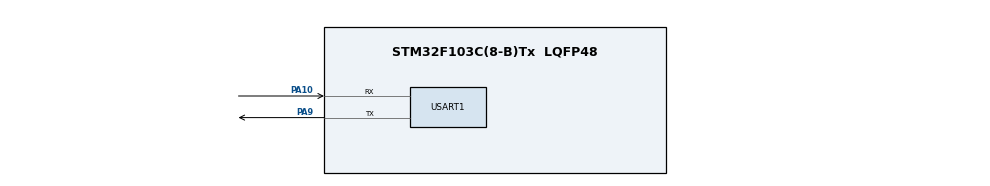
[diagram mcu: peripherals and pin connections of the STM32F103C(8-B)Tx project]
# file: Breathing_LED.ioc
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Mcu.Family=STM32F1
Mcu.Name=STM32F103C(8-B)Tx
Mcu.Package=LQFP48
NVIC.PriorityGroup=NVIC_PRIORITYGROUP_4
PA1.Signal=S_TIM2_CH2
PA10.Mode=Asynchronous
PA10.Signal=USART1_RX
PA13.Mode=Serial_Wire
PA13.Signal=SYS_JTMS-SWDIO
PA14.Mode=Serial_Wire
PA14.Signal=SYS_JTCK-SWCLK
PA9.Mode=Asynchronous
PA9.Signal=USART1_TX
PD0-OSC_IN.Mode=HSE-External-Oscillator
PD0-OSC_IN.Signal=RCC_OSC_IN
PD1-OSC_OUT.Mode=HSE-External-Oscillator
PD1-OSC_OUT.Signal=RCC_OSC_OUT
ProjectManager.HeapSize=0x200
Pr

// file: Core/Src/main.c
/* USER CODE BEGIN Header */
/**
  ******************************************************************************
  * @file           : main.c
  * @brief          : Main program body
  ******************************************************************************
  * @attention
  *
  * Copyright (c) 2026 STMicroelectronics.
  * All rights reserved.
  *
  * This software is licensed under terms that can be found in the LICENSE file
  * in the root directory of this software component.
  * If no LICENSE file comes with this software, it is provided AS-IS.
  *
  ******************************************************************************
  */
/* USER CODE END Header */
#include "main.h"
#include "tim.h"
#include "usart.h"
#include "gpio.h"

/* USER CODE BEGIN Includes */
#include <stdio.h>
/* USER CODE END Includes */

/* USER CODE BEGIN PV */
uint16_t pwmVal = 0;   		//PWM占空比值
uint8_t direction = 1; 		//呼吸方向：1为变亮，0为变暗
uint8_t rxData;        		//接收串口的一个字节数据
uint8_t lightEnable = 1; 	//呼吸灯使能开关，默认开启
/* USER CODE END PV */

void SystemClock_Config(void);

/* USER CODE BEGIN 0 */

#ifdef __GNUC__
  #define PUTCHAR_PROTOTYPE int __io_putchar(int ch)
#else
  #define PUTCHAR_PROTOTYPE int fputc(int ch, FILE *f)
#endif

//重定向libc的printf到UART
PUTCHAR_PROTOTYPE
{
  //使用HAL库的阻塞发送函数
  //&huart1是CubeMX自动生成的串口句柄
  //0xFFFF是超时时间
  HAL_UART_Transmit(&huart1, (uint8_t *)&ch, 1, 0xFFFF);
  return ch;
}

/* USER CODE END 0 */

int main(void)
{

  /* MCU Configuration--------------------------------------------------------*/

  /* Reset of all peripherals, Initializes the Flash interface and the Systick. */
  HAL_Init();

  /* Configure the system clock */
  SystemClock_Config();

  /* Initialize all configured peripherals */
  MX_GPIO_Init();
  MX_TIM2_Init();
  MX_USART1_UART_Init();
  /* USER CODE BEGIN 2 */

  //启动TIM2通道2的PWM输出
  HAL_TIM_PWM_Start(&htim2, TIM_CHANNEL_2);

  //开启串口接收中断，单片机收到1个字节就存到rxData并在回调函数里“通知”程序员
  HAL_UART_Receive_IT(&huart1, &rxData, 1);

  printf("System Start! Send '1' to Enable, '0' to Disable.\r\n");

  /* USER CODE END 2 */

  /* Infinite loop */
  /* USER CODE BEGIN WHILE */
  while (1)
  {
	  if(lightEnable)
	  {
		//呼吸逻辑
		if(direction) 	 pwmVal++;	//亮度+1
		else 	pwmVal--;	//亮度-1

		if(pwmVal > 490) 	direction = 0; 	//接近最大值500时转向
		if(pwmVal < 10)  	direction = 1; 	//接近最小值0时转向

		//更新占空比 (PA1对应TIM2_CH2)
		__HAL_TIM_SET_COMPARE(&htim2, TIM_CHANNEL_2, pwmVal);

		HAL_Delay(5);	//延时5ms调节呼吸速度
	  }
      else
      {
		//关闭灯光：占空比设为0
		__HAL_TIM_SET_COMPARE(&htim2, TIM_CHANNEL_2, 0);
		HAL_Delay(100);	  //降低不运行时的循环频率
	  }

    /* USER CODE END WHILE */

  }
}

void SystemClock_Config(void)
{
  RCC_OscInitTypeDef RCC_OscInitStruct = {0};
  RCC_ClkInitTypeDef RCC_ClkInitStruct = {0};

  /** Initializes the RCC Oscillators according to the specified parameters
  * in the RCC_OscInitTypeDef structure.
  */
  RCC_OscInitStruct.OscillatorType = RCC_OSCILLATORTYPE_HSE;
  RCC_OscInitStruct.HSEState = RCC_HSE_ON;
  RCC_OscInitStruct.HSEPredivValue = RCC_HSE_PREDIV_DIV1;
  RCC_OscInitStruct.HSIState = RCC_HSI_ON;
  RCC_OscInitStruct.PLL.PLLState = RCC_PLL_ON;
  RCC_OscInitStruct.PLL.PLLSource = RCC_PLLSOURCE_HSE;
  RCC_OscInitStruct.PLL.PLLMUL = RCC_PLL_MUL9;
  if (HAL_RCC_OscConfig(&RCC_OscInitStruct) != HAL_OK)
  {
    Error_Handler();
  }

  /** Initializes the CPU, AHB and APB buses clocks
  */
  RCC_ClkInitStruct.ClockType = RCC_CLOCKTYPE_HCLK|RCC_CLOCKTYPE_SYSCLK
                              |RCC_CLOCKTYPE_PCLK1|RCC_CLOCKTYPE_PCLK2;
  RCC_ClkInitStruct.SYSCLKSource = RCC_SYSCLKSOURCE_PLLCLK;
  RCC_ClkInitStruct.AHBCLKDivider = RCC_SYSCLK_DIV1;
  RCC_ClkInitStruct.APB1CLKDivider = RCC_HCLK_DIV2;
  RCC_ClkInitStruct.APB2CLKDivider = RCC_HCLK_DIV1;

  if (HAL_RCC_ClockConfig(&RCC_ClkInitStruct, FLASH_LATENCY_2) != HAL_OK)
  {
    Error_Handler();
  }
}

/* USER CODE BEGIN 4 */

void HAL_UART_RxCpltCallback(UART_HandleTypeDef *huart)
{
  if(huart->Instance == USART1)	  //确认是串口 1
  {
    if(rxData == '1')
	{
      lightEnable = 1;
    }
    else if(rxData == '0')
	{
      lightEnable = 0;
    }
    //HAL库的中断是“一次性”的，必须在回调函数里重新开启
    HAL_UART_Receive_IT(&huart1, &rxData, 1);
  }
}

/* USER CODE END 4 */

void Error_Handler(void)
{
  __disable_irq();
  while (1)
  {
  }
}
